VERSION 5.7 ;
  NOWIREEXTENSIONATPIN ON ;
  DIVIDERCHAR "/" ;
  BUSBITCHARS "[]" ;
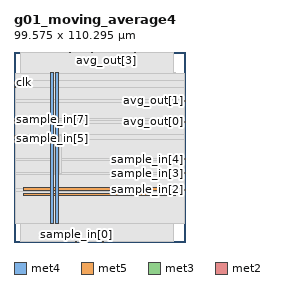
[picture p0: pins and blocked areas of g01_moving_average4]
MACRO g01_moving_average4
  CLASS BLOCK ;
  FOREIGN g01_moving_average4 ;
  ORIGIN 0.000 0.000 ;
  SIZE 99.575 BY 110.295 ;
  PIN VGND
    DIRECTION INOUT ;
    USE GROUND ;
    PORT
      LAYER met4 ;
        RECT 24.340 10.640 25.940 98.160 ;
    END
    PORT
      LAYER met5 ;
        RECT 5.520 30.030 93.840 31.630 ;
    END
  END VGND
  PIN VPWR
    DIRECTION INOUT ;
    USE POWER ;
    PORT
      LAYER met4 ;
        RECT 21.040 10.640 22.640 98.160 ;
    END
    PORT
      LAYER met5 ;
        RECT 5.520 26.730 93.840 28.330 ;
    END
  END VPWR
  PIN avg_out[0]
    DIRECTION OUTPUT ;
    USE SIGNAL ;
    ANTENNADIFFAREA 0.702900 ;
    PORT
      LAYER met3 ;
        RECT 98.975 69.400 99.575 70.000 ;
    END
  END avg_out[0]
  PIN avg_out[1]
    DIRECTION OUTPUT ;
    USE SIGNAL ;
    ANTENNADIFFAREA 0.702900 ;
    PORT
      LAYER met3 ;
        RECT 98.975 81.640 99.575 82.240 ;
    END
  END avg_out[1]
  PIN avg_out[2]
    DIRECTION OUTPUT ;
    USE SIGNAL ;
    ANTENNADIFFAREA 0.702900 ;
    PORT
      LAYER met2 ;
        RECT 70.010 110.015 70.290 110.295 ;
    END
  END avg_out[2]
  PIN avg_out[3]
    DIRECTION OUTPUT ;
    USE SIGNAL ;
    ANTENNADIFFAREA 0.702900 ;
    PORT
      LAYER met2 ;
        RECT 53.450 110.015 53.730 110.295 ;
    END
  END avg_out[3]
  PIN avg_out[4]
    DIRECTION OUTPUT ;
    USE SIGNAL ;
    ANTENNADIFFAREA 0.702900 ;
    PORT
      LAYER met2 ;
        RECT 46.090 110.015 46.370 110.295 ;
    END
  END avg_out[4]
  PIN avg_out[5]
    DIRECTION OUTPUT ;
    USE SIGNAL ;
    ANTENNADIFFAREA 0.702900 ;
    PORT
      LAYER met2 ;
        RECT 39.650 110.015 39.930 110.295 ;
    END
  END avg_out[5]
  PIN avg_out[6]
    DIRECTION OUTPUT ;
    USE SIGNAL ;
    ANTENNADIFFAREA 0.702900 ;
    PORT
      LAYER met2 ;
        RECT 32.290 110.015 32.570 110.295 ;
    END
  END avg_out[6]
  PIN avg_out[7]
    DIRECTION OUTPUT ;
    USE SIGNAL ;
    ANTENNADIFFAREA 0.702900 ;
    PORT
      LAYER met2 ;
        RECT 45.170 110.015 45.450 110.295 ;
    END
  END avg_out[7]
  PIN clk
    DIRECTION INPUT ;
    USE SIGNAL ;
    ANTENNAGATEAREA 0.852000 ;
    PORT
      LAYER met3 ;
        RECT 0.000 92.520 0.600 93.120 ;
    END
  END clk
  PIN rst_n
    DIRECTION INPUT ;
    USE SIGNAL ;
    ANTENNAGATEAREA 0.159000 ;
    PORT
      LAYER met3 ;
        RECT 0.000 91.160 0.600 91.760 ;
    END
  END rst_n
  PIN sample_in[0]
    DIRECTION INPUT ;
    USE SIGNAL ;
    ANTENNAGATEAREA 0.213000 ;
    PORT
      LAYER met2 ;
        RECT 35.970 0.000 36.250 0.280 ;
    END
  END sample_in[0]
  PIN sample_in[1]
    DIRECTION INPUT ;
    USE SIGNAL ;
    ANTENNAGATEAREA 0.213000 ;
    PORT
      LAYER met2 ;
        RECT 51.610 0.000 51.890 0.280 ;
    END
  END sample_in[1]
  PIN sample_in[2]
    DIRECTION INPUT ;
    USE SIGNAL ;
    ANTENNAGATEAREA 0.213000 ;
    PORT
      LAYER met3 ;
        RECT 98.975 29.960 99.575 30.560 ;
    END
  END sample_in[2]
  PIN sample_in[3]
    DIRECTION INPUT ;
    USE SIGNAL ;
    ANTENNAGATEAREA 0.213000 ;
    PORT
      LAYER met3 ;
        RECT 98.975 39.480 99.575 40.080 ;
    END
  END sample_in[3]
  PIN sample_in[4]
    DIRECTION INPUT ;
    USE SIGNAL ;
    ANTENNAGATEAREA 0.213000 ;
    PORT
      LAYER met3 ;
        RECT 98.975 47.640 99.575 48.240 ;
    END
  END sample_in[4]
  PIN sample_in[5]
    DIRECTION INPUT ;
    USE SIGNAL ;
    ANTENNAGATEAREA 0.213000 ;
    PORT
      LAYER met3 ;
        RECT 0.000 59.880 0.600 60.480 ;
    END
  END sample_in[5]
  PIN sample_in[6]
    DIRECTION INPUT ;
    USE SIGNAL ;
    ANTENNAGATEAREA 0.213000 ;
    PORT
      LAYER met3 ;
        RECT 0.000 61.240 0.600 61.840 ;
    END
  END sample_in[6]
  PIN sample_in[7]
    DIRECTION INPUT ;
    USE SIGNAL ;
    ANTENNAGATEAREA 0.213000 ;
    PORT
      LAYER met3 ;
        RECT 0.000 70.760 0.600 71.360 ;
    END
  END sample_in[7]
  PIN valid_in
    DIRECTION INPUT ;
    USE SIGNAL ;
    ANTENNAGATEAREA 0.196500 ;
    PORT
      LAYER met3 ;
        RECT 0.000 89.800 0.600 90.400 ;
    END
  END valid_in
  PIN valid_out
    DIRECTION OUTPUT ;
    USE SIGNAL ;
    ANTENNADIFFAREA 0.702900 ;
    PORT
      LAYER met2 ;
        RECT 66.330 110.015 66.610 110.295 ;
    END
  END valid_out
  OBS
      LAYER nwell ;
        RECT 5.330 10.795 94.030 98.005 ;
      LAYER li1 ;
        RECT 5.520 10.795 93.840 98.005 ;
      LAYER met1 ;
        RECT 3.750 10.640 93.840 98.160 ;
      LAYER met2 ;
        RECT 3.770 109.735 32.010 110.015 ;
        RECT 32.850 109.735 39.370 110.015 ;
        RECT 40.210 109.735 44.890 110.015 ;
        RECT 45.730 109.735 45.810 110.015 ;
        RECT 46.650 109.735 53.170 110.015 ;
        RECT 54.010 109.735 66.050 110.015 ;
        RECT 66.890 109.735 69.730 110.015 ;
        RECT 70.570 109.735 92.370 110.015 ;
        RECT 3.770 0.560 92.370 109.735 ;
        RECT 3.770 0.280 35.690 0.560 ;
        RECT 36.530 0.280 51.330 0.560 ;
        RECT 52.170 0.280 92.370 0.560 ;
      LAYER met3 ;
        RECT 0.600 93.520 98.975 98.085 ;
        RECT 1.000 89.400 98.975 93.520 ;
        RECT 0.600 82.640 98.975 89.400 ;
        RECT 0.600 81.240 98.575 82.640 ;
        RECT 0.600 71.760 98.975 81.240 ;
        RECT 1.000 70.400 98.975 71.760 ;
        RECT 1.000 70.360 98.575 70.400 ;
        RECT 0.600 69.000 98.575 70.360 ;
        RECT 0.600 62.240 98.975 69.000 ;
        RECT 1.000 59.480 98.975 62.240 ;
        RECT 0.600 48.640 98.975 59.480 ;
        RECT 0.600 47.240 98.575 48.640 ;
        RECT 0.600 40.480 98.975 47.240 ;
        RECT 0.600 39.080 98.575 40.480 ;
        RECT 0.600 30.960 98.975 39.080 ;
        RECT 0.600 29.560 98.575 30.960 ;
        RECT 0.600 10.715 98.975 29.560 ;
      LAYER met4 ;
        RECT 23.295 39.615 23.940 61.705 ;
        RECT 26.340 39.615 27.305 61.705 ;
  END
END g01_moving_average4
END LIBRARY

